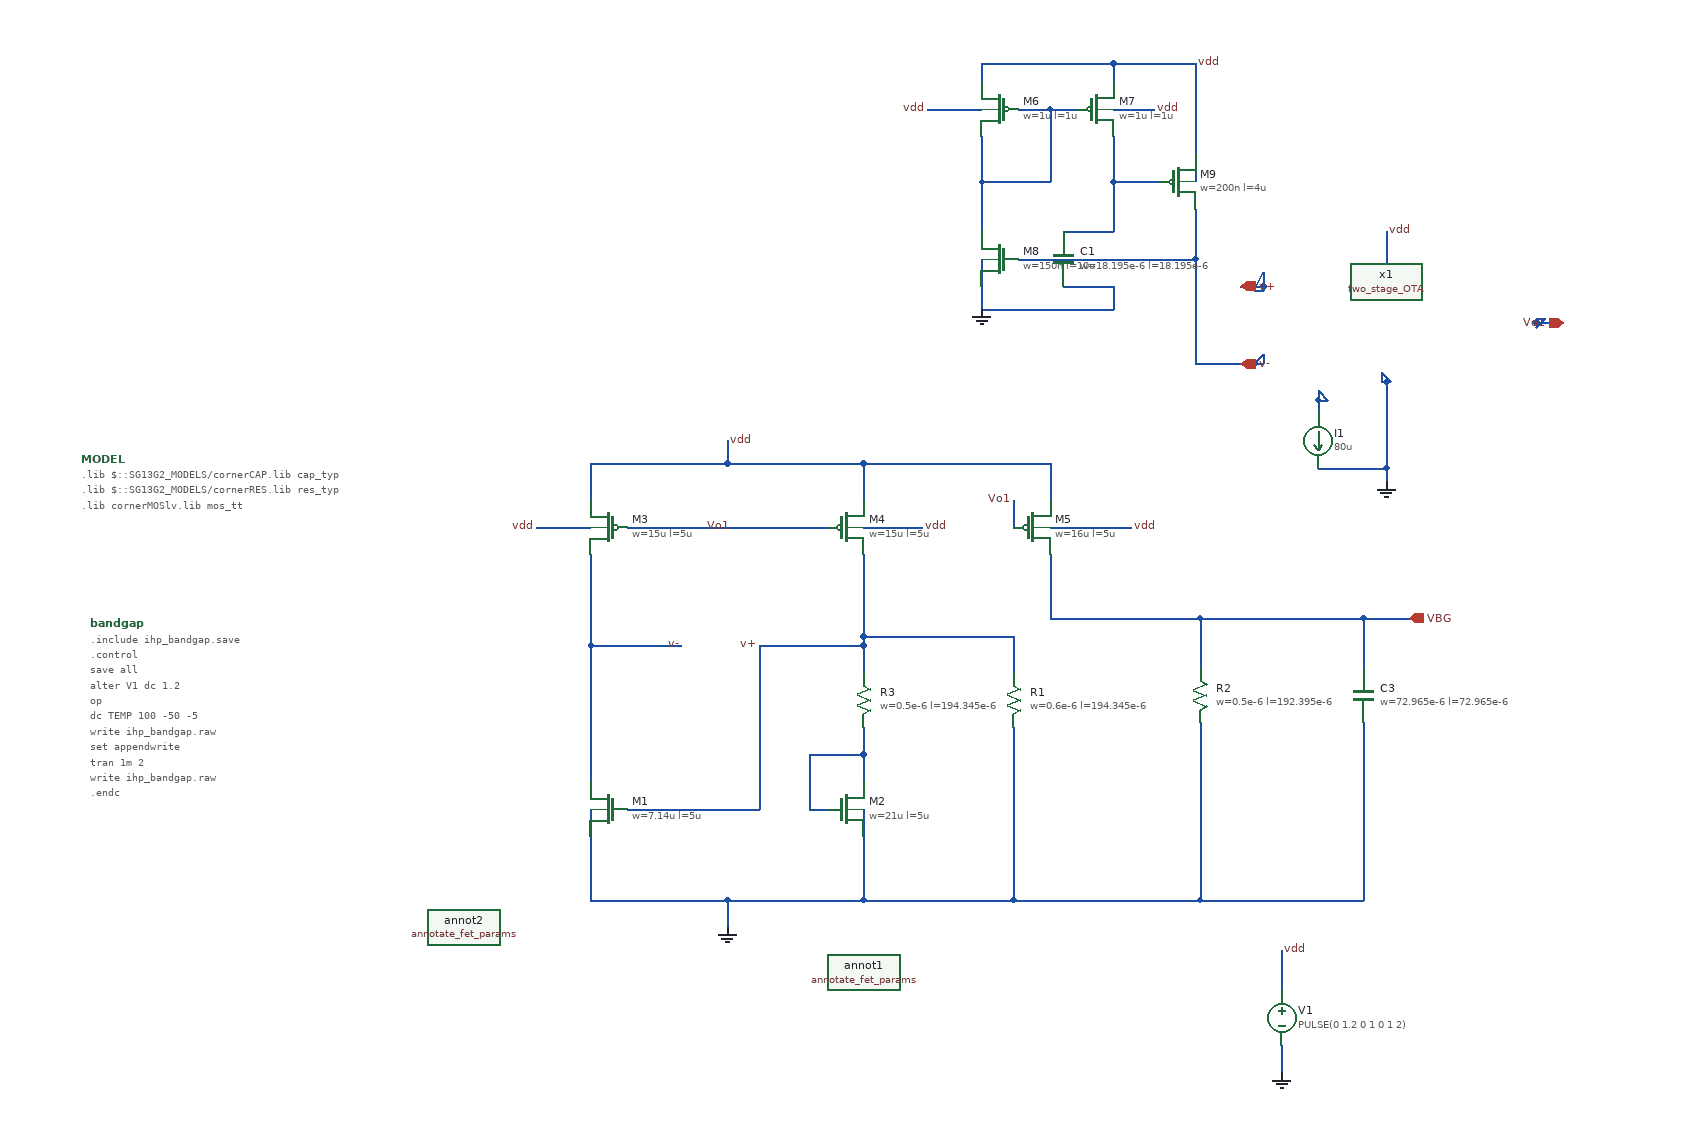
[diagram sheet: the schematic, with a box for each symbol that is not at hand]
v {xschem version=3.4.8RC file_version=1.2}
G {}
K {}
V {}
S {}
F {}
E {}
B 2 1475.3515625 -384.21875 2275.3515625 15.78125 {flags=graph
y1=1.1
y2=1.3
ypos1=0
ypos2=2
divy=5
subdivy=1
unity=1

x2=104.62392
divx=5
subdivx=1
xlabmag=1.0
ylabmag=1.0


dataset=-1
unitx=1
logx=0
logy=0
x1=-45.376083
color=7
node=vdd
rawfile=$netlist_dir/ihp_bandgap.raw}
B 2 1475.3515625 25.78125 2275.3515625 425.78125 {flags=graph
y1=0.6
y2=0.61
ypos1=0
ypos2=2
divy=5
subdivy=1
unity=1

x2=104.62392
divx=5
subdivx=1
xlabmag=1.0
ylabmag=1.0
node=vbg
color=4
dataset=-1
unitx=1
logx=0
logy=0
x1=-45.376083}
N 980 325 980 370 {
lab=vdd}
N 980 430 980 460 {
lab=GND}
N 460 170 480 170 {
lab=#net1}
N 460 110 460 170 {
lab=#net1}
N 460 110 520 110 {
lab=#net1}
N 220 170 220 270 {
lab=GND}
N 370 270 520 270 {
lab=GND}
N 220 -10 320 -10 {
lab=v-}
N 370 -235 370 -210 {
lab=vdd}
N 220 -210 370 -210 {
lab=vdd}
N 220 -110 220 -10 {
lab=v-}
N 520 -20 520 -10 {
lab=v+}
N 520 -10 520 20 {
lab=v+}
N 520 170 520 270 {
lab=GND}
N 520 110 520 140 {
lab=#net1}
N 520 80 520 110 {
lab=#net1}
N 370 270 370 300 {
lab=GND}
N 220 270 370 270 {
lab=GND}
N 260 -140 480 -140 {
lab=Vo1}
N 685 -170 685 -140 {
lab=Vo1}
N 520 -20 685 -20 {
lab=v+}
N 1070 -40 1120 -40 {
lab=VBG}
N 725 -110 725 -40 {
lab=VBG}
N 405 -10 520 -10 {
lab=v+}
N 520 -110 520 -20 {
lab=v+}
N 685 -20 685 20 {
lab=v+}
N 520 270 685 270 {
lab=GND}
N 685 80 685 270 {
lab=GND}
N 520 -210 725 -210 {
lab=vdd}
N 1070 75 1070 270 {
lab=GND}
N 890 270 1070 270 {
lab=GND}
N 1070 -40 1070 15 {
lab=VBG}
N 890 -40 1070 -40 {
lab=VBG}
N 725 -210 725 -170 {
lab=vdd}
N 725 -140 815 -140 {
lab=vdd}
N 520 -210 520 -170 {
lab=vdd}
N 370 -210 520 -210 {
lab=vdd}
N 520 -140 585 -140 {
lab=vdd}
N 220 -210 220 -170 {
lab=vdd}
N 160 -140 220 -140 {
lab=vdd}
N 220 -10 220 140 {
lab=v-}
N 260 170 405 170 {
lab=v+}
N 405 -10 405 170 {
lab=v+}
N 890 -40 890 15 {
lab=VBG}
N 725 -40 890 -40 {
lab=VBG}
N 890 75 890 270 {
lab=GND}
N 685 270 890 270 {
lab=GND}
N 650 -520 650 -465 {
lab=#net2}
N 795 -650 885 -650 {
lab=vdd}
N 725 -600 755 -600 {
lab=#net2}
N 650 -520 725 -520 {
lab=#net2}
N 650 -570 650 -520 {
lab=#net2}
N 725 -600 725 -520 {
lab=#net2}
N 690 -600 725 -600 {
lab=#net2}
N 650 -435 650 -380 {
lab=GND}
N 795 -520 795 -465 {
lab=#net3}
N 650 -380 795 -380 {
lab=GND}
N 795 -405 795 -380 {
lab=GND}
N 690 -435 885 -435 {
lab=v-}
N 885 -650 885 -520 {
lab=vdd}
N 795 -520 845 -520 {
lab=#net3}
N 795 -570 795 -520 {
lab=#net3}
N 885 -435 885 -320 {
lab=v-}
N 885 -490 885 -435 {
lab=v-}
N 1260 -365 1290 -365 {
lab=Vo1}
N 1095 -465 1095 -430 {
lab=vdd}
N 1020 -205 1095 -205 {
lab=GND}
N 1095 -205 1095 -190 {
lab=GND}
N 1095 -300 1095 -205 {
lab=GND}
N 935 -405 960 -405 {
lab=v+}
N 950 -320 960 -320 {
lab=v-}
N 590 -600 650 -600 {
lab=vdd}
N 795 -600 840 -600 {
lab=vdd}
N 795 -650 795 -630 {
lab=vdd}
N 650 -650 795 -650 {
lab=vdd}
N 650 -650 650 -630 {
lab=vdd}
N 740 -465 795 -465 {
lab=#net3}
N 740 -405 795 -405 {
lab=GND}
N 1260 -365 1260 -360 {lab=Vo1}
N 1260 -370 1260 -365 {lab=Vo1}
N 1260 -360 1270 -370 {lab=Vo1}
N 1260 -370 1270 -370 {lab=Vo1}
N 1090 -310 1100 -300 {lab=GND}
N 1095 -300 1100 -300 {lab=GND}
N 1090 -300 1095 -300 {lab=GND}
N 1090 -310 1090 -300 {lab=GND}
N 1020 -280 1020 -265 {lab=#net4}
N 1020 -290 1030 -280 {lab=#net4}
N 1020 -280 1030 -280 {lab=#net4}
N 1020 -290 1020 -280 {lab=#net4}
N 950 -320 960 -330 {lab=v-}
N 885 -320 950 -320 {
lab=v-}
N 960 -330 960 -320 {lab=v-}
N 960 -405 960 -400 {lab=v+}
N 960 -420 960 -405 {lab=v+}
N 950 -400 960 -420 {lab=v+}
N 950 -400 960 -400 {lab=v+}
C {devices/code_shown.sym} -340 -215 0 0 {name=MODEL only_toplevel=true
format="tcleval( @value )"
value="
.lib $::SG13G2_MODELS/cornerCAP.lib cap_typ
.lib $::SG13G2_MODELS/cornerRES.lib res_typ
.lib cornerMOSlv.lib mos_tt
"}
C {devices/code_shown.sym} -330 -33.828125 0 0 {name=bandgap only_toplevel=true value="

.include ihp_bandgap.save


.control
save all
alter V1 dc 1.2            
op
dc TEMP 100 -50 -5
write ihp_bandgap.raw
set appendwrite 
tran 1m 2 
write ihp_bandgap.raw
  

.endc
"
}
C {vsource.sym} 980 400 0 0 {name=V1 value="PULSE(0 1.2 0 1 0 1 2)" savecurrent=false}
C {lab_pin.sym} 980 325 0 1 {name=p6 sig_type=std_logic lab=vdd}
C {gnd.sym} 980 460 0 0 {name=l18 lab=GND}
C {sg13g2_pr/sg13_lv_nmos.sym} 240 170 2 0 {name=M1
l=5u
w=7.14u
ng=4
m=1
model=sg13_lv_nmos
spiceprefix=X
}
C {sg13g2_pr/sg13_lv_nmos.sym} 500 170 2 1 {name=M2
l=5u
w=21u
ng=8
m=1
model=sg13_lv_nmos
spiceprefix=X
}
C {gnd.sym} 370 300 0 0 {name=l3 lab=GND}
C {sg13g2_pr/sg13_lv_pmos.sym} 240 -140 0 1 {name=M3
l=5u
w=15u
ng=8
m=1
model=sg13_lv_pmos
spiceprefix=X
}
C {sg13g2_pr/sg13_lv_pmos.sym} 500 -140 0 0 {name=M4
l=5u
w=15u
ng=8
m=1
model=sg13_lv_pmos
spiceprefix=X
}
C {lab_pin.sym} 370 -235 0 1 {name=p2 sig_type=std_logic lab=vdd}
C {lab_pin.sym} 320 -10 3 0 {name=p3 sig_type=std_logic lab=v-}
C {lab_pin.sym} 405 -10 0 0 {name=p8 sig_type=std_logic lab=v+}
C {lab_pin.sym} 375 -140 1 1 {name=p9 sig_type=std_logic lab=Vo1}
C {sg13g2_pr/sg13_lv_pmos.sym} 705 -140 0 0 {name=M5
l=5u
w=16u
ng=8
m=1
model=sg13_lv_pmos
spiceprefix=X
}
C {opin.sym} 1120 -40 0 0 {name=p11 lab=VBG}
C {lab_pin.sym} 685 -170 2 1 {name=p12 sig_type=std_logic lab=Vo1}
C {lab_pin.sym} 160 -140 0 0 {name=p13 sig_type=std_logic lab=vdd}
C {lab_pin.sym} 585 -140 0 1 {name=p14 sig_type=std_logic lab=vdd}
C {lab_pin.sym} 815 -140 0 1 {name=p15 sig_type=std_logic lab=vdd}
C {sg13g2_pr/cap_cmim.sym} 1070 45 0 0 {name=C3
model=cap_cmim
w=72.965e-6
l=72.965e-6
m=1
spiceprefix=X}
C {sg13g2_pr/rppd.sym} 520 50 0 0 {name=R3
w=0.5e-6
l=194.345e-6
model=rppd
spiceprefix=X
b=0
m=1
}
C {sg13g2_pr/rppd.sym} 685 50 0 0 {name=R1
w=0.6e-6
l=194.345e-6
model=rppd
spiceprefix=X
b=0
m=1
}
C {sg13g2_pr/rppd.sym} 890 45 0 0 {name=R2
w=0.5e-6
l=192.395e-6
model=rppd
spiceprefix=X
b=0
m=1
}
C {launcher.sym} 1261.40625 -83.28125 0 0 {name=h5
descr="load DC" 
tclcommand="xschem raw_read $netlist_dir/bgr_temp.raw dc"
}
C {launcher.sym} 1261.40625 -38.28125 0 0 {name=h1
descr="load Transient" 
tclcommand="xschem raw_read $netlist_dir/bandgap_transient.raw tran"
}
C {sg13g2_pr/annotate_fet_params.sym} 520 350 0 0 {name=annot1 ref=M2}
C {sg13g2_pr/sg13_lv_nmos.sym} 670 -435 2 0 {name=M8
l=10u
w=150n
ng=1
m=1
model=sg13_lv_nmos
spiceprefix=X
}
C {sg13g2_pr/sg13_lv_pmos.sym} 670 -600 0 1 {name=M6
l=1u
w=1u
ng=1
m=1
model=sg13_lv_pmos
spiceprefix=X
}
C {sg13g2_pr/sg13_lv_pmos.sym} 775 -600 0 0 {name=M7
l=1u
w=1u
ng=1
m=1
model=sg13_lv_pmos
spiceprefix=X
}
C {gnd.sym} 650 -380 0 0 {name=l1 lab=GND}
C {sg13g2_pr/sg13_lv_pmos.sym} 865 -520 0 0 {name=M9
l=4u
w=200n
ng=1
m=1
model=sg13_lv_pmos
spiceprefix=X
}
C {lab_pin.sym} 885 -650 0 1 {name=p5 sig_type=std_logic lab=vdd}
C {lab_pin.sym} 1095 -465 0 1 {name=p1 sig_type=std_logic lab=vdd}
C {gnd.sym} 1095 -190 0 1 {name=l4 lab=GND}
C {isource.sym} 1020 -235 0 1 {name=I1 value=80u}
C {iopin.sym} 935 -405 0 1 {name=p16 lab=v+}
C {iopin.sym} 935 -320 3 1 {name=p7 lab=v-}
C {iopin.sym} 1290 -365 0 0 {name=p10 lab=Vo1}
C {lab_pin.sym} 840 -600 0 1 {name=p4 sig_type=std_logic lab=vdd}
C {lab_pin.sym} 590 -600 0 0 {name=p17 sig_type=std_logic lab=vdd}
C {sg13g2_pr/cap_cmim.sym} 740 -435 0 0 {name=C1
model=cap_cmim
w=18.195e-6
l=18.195e-6
m=1
spiceprefix=X}
C {/foss/designs/TO_Apr2025/bandgap_ref_cmos/design_data/xschem/part_1_OTA/two_stage_OTA.sym} 1110 -370 0 0 {name=x1}
C {sg13g2_pr/annotate_fet_params.sym} 80 300 0 0 {name=annot2 ref=M3}
